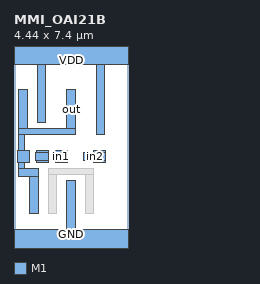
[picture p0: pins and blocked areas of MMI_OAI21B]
MACRO MMI_OAI21B
	CLASS CORE ;
	FOREIGN MMI_OAI21B 0 0 ;
	SIZE 4.44 BY 7.4 ;
	SYMMETRY X Y ;
	SITE CORE1 ;
	PIN out
		DIRECTION output ;
		USE SIGNAL ;
		PORT
			LAYER M1 ;
			RECT 0.18 4.41 0.52 5.94 ;
			LAYER M1 ;
			RECT 2.05 4.41 2.39 5.94 ;
			LAYER M1 ;
			RECT 0.18 4.18 2.39 4.41 ;
			LAYER M1 ;
			RECT 0.18 3.555 0.41 4.18 ;
			LAYER M1 ;
			RECT 0.145 3.105 0.595 3.555 ;
			LAYER M1 ;
			RECT 0.18 2.865 0.41 3.105 ;
			LAYER M1 ;
			RECT 0.18 2.545 0.95 2.865 ;
			LAYER M1 ;
			RECT 0.61 1.105 0.95 2.545 ;
		END
		AntennaDiffArea 2.76 ;
	END out
	PIN in1
		DIRECTION input ;
		USE SIGNAL ;
		PORT
			LAYER M1 ;
			RECT 1.625 3.5 2.075 3.555 ;
			LAYER M1 ;
			RECT 1.57 3.16 2.075 3.5 ;
			LAYER M1 ;
			RECT 1.625 3.105 2.075 3.16 ;
		END
		AntennaGateArea 0.9936 ;
	END in1
	PIN GND
		DIRECTION inout ;
		USE GROUND ;
		PORT
			LAYER M1 ;
			RECT 2.05 0.505 2.39 2.385 ;
			LAYER M1 ;
			RECT 2.05 0.5 2.82 0.505 ;
			LAYER M1 ;
			RECT 0 -0.5 4.44 0.5 ;
		END
	END GND
	PIN in2
		DIRECTION input ;
		USE SIGNAL ;
		PORT
			LAYER M1 ;
			RECT 3.105 3.5 3.555 3.555 ;
			LAYER M1 ;
			RECT 2.72 3.16 3.555 3.5 ;
			LAYER M1 ;
			RECT 3.105 3.105 3.555 3.16 ;
		END
		AntennaGateArea 0.9936 ;
	END in2
	PIN VDD
		DIRECTION inout ;
		USE POWER ;
		PORT
			LAYER M1 ;
			RECT 0 6.9 4.44 7.9 ;
			LAYER M1 ;
			RECT 0.9 4.66 1.24 6.9 ;
			LAYER M1 ;
			RECT 3.2 4.18 3.54 6.9 ;
		END
	END VDD
	PIN in0
		DIRECTION input ;
		USE SIGNAL ;
		PORT
			LAYER M1 ;
			RECT 0.885 3.5 1.335 3.555 ;
			LAYER M1 ;
			RECT 0.825 3.16 1.335 3.5 ;
			LAYER M1 ;
			RECT 0.885 3.105 1.335 3.16 ;
		END
		AntennaGateArea 0.6624 ;
	END in0
	OBS
		LAYER M1 ;
		RECT 1.33 2.635 3.11 2.865 ;
		LAYER M1 ;
		RECT 1.33 1.105 1.67 2.635 ;
		LAYER M1 ;
		RECT 2.77 1.105 3.11 2.635 ;
	END
END MMI_OAI21B
